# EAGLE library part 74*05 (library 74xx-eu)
Hex INVERTER, open collector

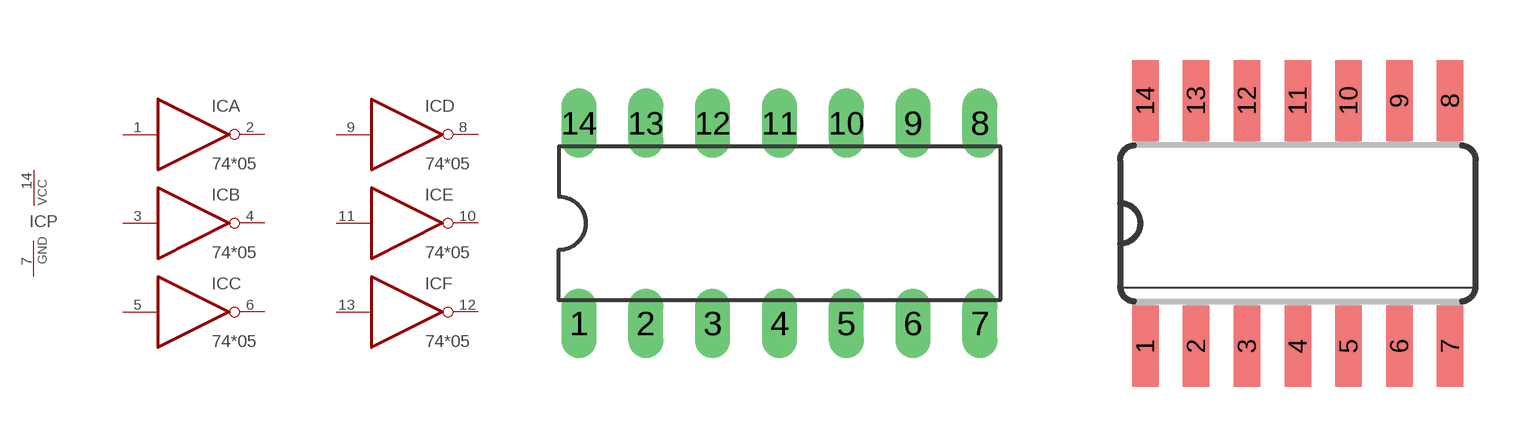
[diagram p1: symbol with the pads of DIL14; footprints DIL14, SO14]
Designator prefix IC; gates A=7405 B=7405 C=7405 D=7405 E=7405 F=7405 P=PWRN

## 7405N, 74ALS05N, 74HCT05N, 74LS05N, 74S05N  [DIL14]
1  A:I  in
2  A:O  oc
3  B:I  in
4  B:O  oc
5  C:I  in
6  C:O  oc
7  P:GND  pwr
8  D:O  oc
9  D:I  in
10  E:O  oc
11  E:I  in
12  F:O  oc
13  F:I  in
14  P:VCC  pwr

## 7405D, 74ALS05D, 74HCT05D, 74LS05D, 74S05D  [SO14]
Pads as for DIL14

## 7405FK, 74ALS05FK, 74HCT05FK, 74LS05FK, 74S05FK  [LCC20]
2  A:I  in
3  A:O  oc
4  B:I  in
6  B:O  oc
8  C:I  in
9  C:O  oc
10  P:GND  pwr
12  D:O  oc
13  D:I  in
14  E:O  oc
16  E:I  in
18  F:O  oc
19  F:I  in
20  P:VCC  pwr

## Footprint DIL14 (pad centres in mm)
Dual In Line Package
drill 0.813 long: 1 -7.62,-3.81; 2 -5.08,-3.81; 3 -2.54,-3.81; 4 0,-3.81; 5 2.54,-3.81; 6 5.08,-3.81; 7 7.62,-3.81; 8 7.62,3.81; 9 5.08,3.81; 10 2.54,3.81; 11 0,3.81; 12 -2.54,3.81; 13 -5.08,3.81; 14 -7.62,3.81

## Footprint SO14 (pad centres in mm)
Small Outline package 150 mil
smd 0.66 x 2.032: 1 -3.81,-3.073; 2 -2.54,-3.073; 3 -1.27,-3.073; 4 0,-3.073; 5 1.27,-3.073; 6 2.54,-3.073; 7 3.81,-3.073; 8 3.81,3.073; 9 2.54,3.073; 10 1.27,3.073; 11 0,3.073; 12 -1.27,3.073; 13 -2.54,3.073; 14 -3.81,3.073

## Footprint LCC20 (pad centres in mm)
Leadless Chip Carrier Ceramic Package
smd 0.8 x 3.4: 1 0,3.8
smd 0.8 x 2: 2 -1.27,4.5; 3 -2.54,4.5; 9 -2.54,-4.5; 10 -1.27,-4.5; 11 0,-4.5; 12 1.27,-4.5; 13 2.54,-4.5; 19 2.54,4.5; 20 1.27,4.5
smd 2 x 0.8: 4 -4.5,2.54; 5 -4.5,1.27; 6 -4.5,0; 7 -4.5,-1.27; 8 -4.5,-2.54; 14 4.5,-2.54; 15 4.5,-1.27; 16 4.5,0; 17 4.5,1.27; 18 4.5,2.54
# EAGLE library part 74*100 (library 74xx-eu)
8-bit bistable LATCH

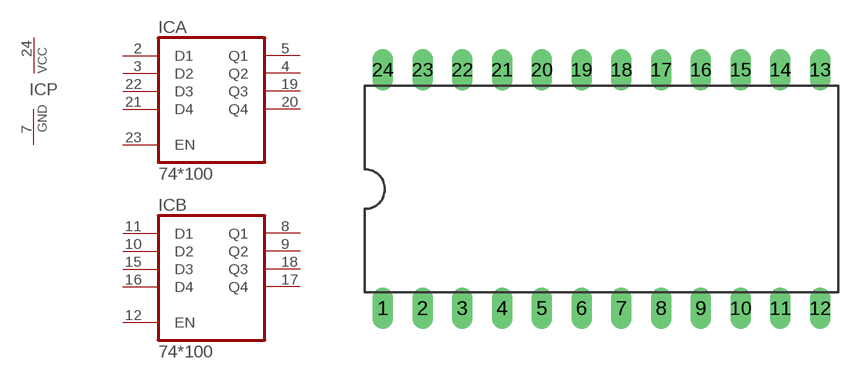
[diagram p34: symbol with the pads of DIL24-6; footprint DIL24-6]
Designator prefix IC; gates A=74100 B=74100 P=PWRN

## 74100N  [DIL24-6]
2  A:D1  in
3  A:D2  in
4  A:Q2  out
5  A:Q1  out
7  P:GND  pwr
8  B:Q1  out
9  B:Q2  out
10  B:D2  in
11  B:D1  in
12  B:EN  in
15  B:D3  in
16  B:D4  in
17  B:Q4  out
18  B:Q3  out
19  A:Q3  out
20  A:Q4  out
21  A:D4  in
22  A:D3  in
23  A:EN  in
24  P:VCC  pwr

## Footprint DIL24-6 (pad centres in mm)
Dual In Line Package 0.6 inch
drill 0.813 long: 1 -13.97,-7.62; 2 -11.43,-7.62; 3 -8.89,-7.62; 4 -6.35,-7.62; 5 -3.81,-7.62; 6 -1.27,-7.62; 7 1.27,-7.62; 8 3.81,-7.62; 9 6.35,-7.62; 10 8.89,-7.62; 11 11.43,-7.62; 12 13.97,-7.62; 13 13.97,7.62; 14 11.43,7.62; 15 8.89,7.62; 16 6.35,7.62; 17 3.81,7.62; 18 1.27,7.62; 19 -1.27,7.62; 20 -3.81,7.62; 21 -6.35,7.62; 22 -8.89,7.62; 23 -11.43,7.62; 24 -13.97,7.62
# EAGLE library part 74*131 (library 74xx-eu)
3-line to 8-line DECODER/DEMULTIPLEXER, address register

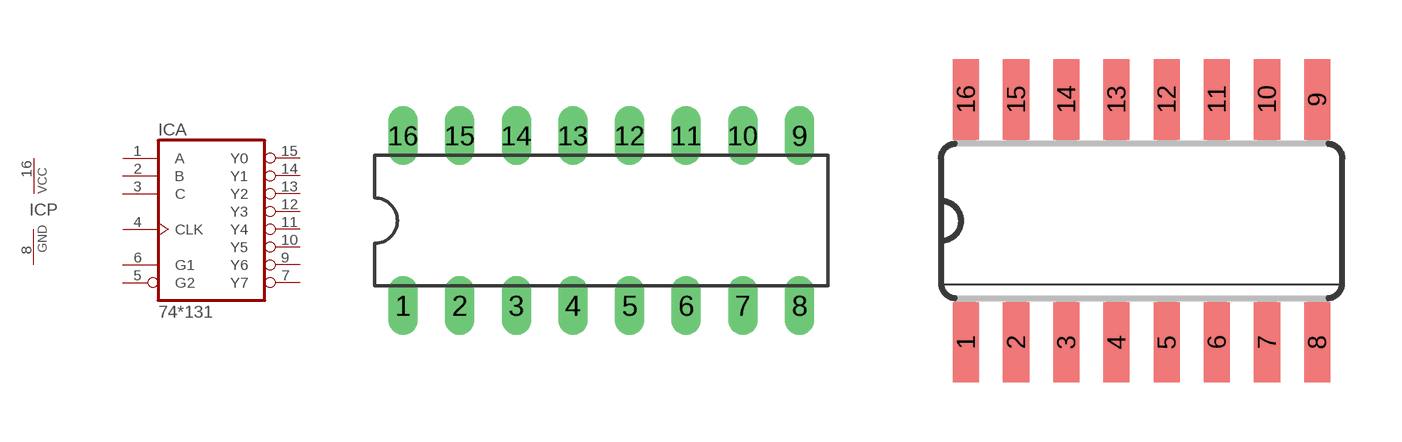
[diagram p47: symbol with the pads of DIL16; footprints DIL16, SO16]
Designator prefix IC; gates A=74131 P=PWRN

## 74131N, 74HC131N  [DIL16]
1  A:A  in
2  A:B  in
3  A:C  in
4  A:CLK  in
5  A:G2  in
6  A:G1  in
7  A:Y7  out
8  P:GND  pwr
9  A:Y6  out
10  A:Y5  out
11  A:Y4  out
12  A:Y3  out
13  A:Y2  out
14  A:Y1  out
15  A:Y0  out
16  P:VCC  pwr

## 74HC131D  [SO16]
Pads as for DIL16

## Footprint DIL16 (pad centres in mm)
Dual In Line Package
drill 0.813 long: 1 -8.89,-3.81; 2 -6.35,-3.81; 3 -3.81,-3.81; 4 -1.27,-3.81; 5 1.27,-3.81; 6 3.81,-3.81; 7 6.35,-3.81; 8 8.89,-3.81; 9 8.89,3.81; 10 6.35,3.81; 11 3.81,3.81; 12 1.27,3.81; 13 -1.27,3.81; 14 -3.81,3.81; 15 -6.35,3.81; 16 -8.89,3.81

## Footprint SO16 (pad centres in mm)
Small Outline package 150 mil
smd 0.66 x 2.032: 1 -4.445,-3.073; 2 -3.175,-3.073; 3 -1.905,-3.073; 4 -0.635,-3.073; 5 0.635,-3.073; 6 1.905,-3.073; 7 3.175,-3.073; 8 4.445,-3.073; 9 4.445,3.073; 10 3.175,3.073; 11 1.905,3.073; 12 0.635,3.073; 13 -0.635,3.073; 14 -1.905,3.073; 15 -3.175,3.073; 16 -4.445,3.073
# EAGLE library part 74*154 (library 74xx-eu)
4-line to 16-line data SELECTOR/MULTIPLEXER

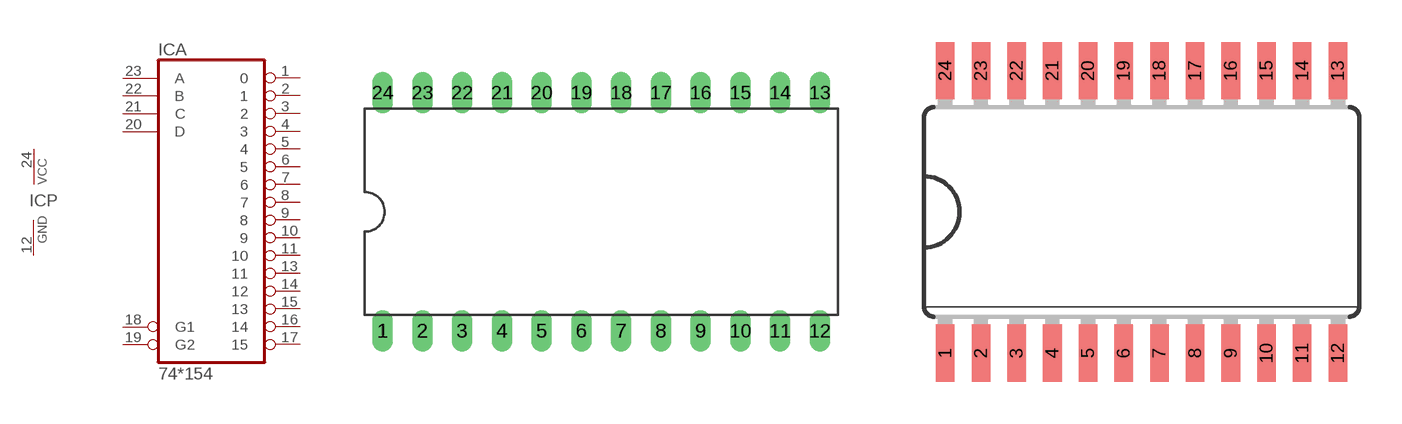
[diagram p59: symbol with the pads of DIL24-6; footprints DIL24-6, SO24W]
Designator prefix IC; gates A=74154 P=PWRN

## 74154N, 74HC154N, 74HCT154N  [DIL24-6]
1  A:0  out
2  A:1  out
3  A:2  out
4  A:3  out
5  A:4  out
6  A:5  out
7  A:6  out
8  A:7  out
9  A:8  out
10  A:9  out
11  A:10  out
12  P:GND  pwr
13  A:11  out
14  A:12  out
15  A:13  out
16  A:14  out
17  A:15  out
18  A:G1  in
19  A:G2  in
20  A:D  in
21  A:C  in
22  A:B  in
23  A:A  in
24  P:VCC  pwr

## 74154DW, 74HC154DW, 74HCT154DW  [SO24W]
Pads as for DIL24-6

## Footprint DIL24-6 (pad centres in mm)
Dual In Line Package 0.6 inch
drill 0.813 long: 1 -13.97,-7.62; 2 -11.43,-7.62; 3 -8.89,-7.62; 4 -6.35,-7.62; 5 -3.81,-7.62; 6 -1.27,-7.62; 7 1.27,-7.62; 8 3.81,-7.62; 9 6.35,-7.62; 10 8.89,-7.62; 11 11.43,-7.62; 12 13.97,-7.62; 13 13.97,7.62; 14 11.43,7.62; 15 8.89,7.62; 16 6.35,7.62; 17 3.81,7.62; 18 1.27,7.62; 19 -1.27,7.62; 20 -3.81,7.62; 21 -6.35,7.62; 22 -8.89,7.62; 23 -11.43,7.62; 24 -13.97,7.62

## Footprint SO24W (pad centres in mm)
Wide Small Outline package 300 mil
smd 0.66 x 2.032: 1 -6.985,-5.029; 2 -5.715,-5.029; 3 -4.445,-5.029; 4 -3.175,-5.029; 5 -1.905,-5.029; 6 -0.635,-5.029; 7 0.635,-5.029; 8 1.905,-5.029; 9 3.175,-5.029; 10 4.445,-5.029; 11 5.715,-5.029; 12 6.985,-5.029; 13 6.985,5.029; 14 5.715,5.029; 15 4.445,5.029; 16 3.175,5.029; 17 1.905,5.029; 18 0.635,5.029; 19 -0.635,5.029; 20 -1.905,5.029; 21 -3.175,5.029; 22 -4.445,5.029; 23 -5.715,5.029; 24 -6.985,5.029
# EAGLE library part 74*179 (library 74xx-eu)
4-bit parallel access SHIFT REGISTER

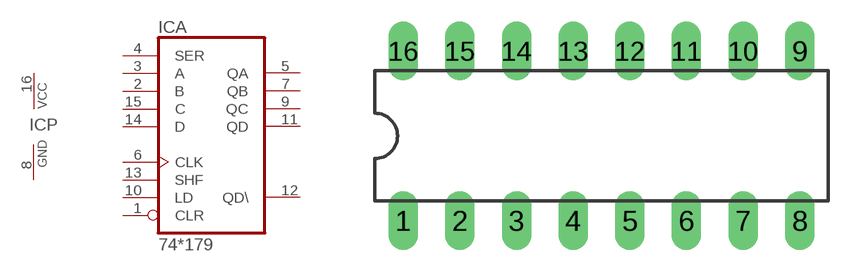
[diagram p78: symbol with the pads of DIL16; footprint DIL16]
Designator prefix IC; gates A=74179 P=PWRN

## 74179N  [DIL16]
1  A:CLR  in
2  A:B  in
3  A:A  in
4  A:SER  in
5  A:QA  out
6  A:CLK  in
7  A:QB  out
8  P:GND  pwr
9  A:QC  out
10  A:LD  in
11  A:QD  out
12  A:QD\  out
13  A:SHF  in
14  A:D  in
15  A:C  in
16  P:VCC  pwr

## Footprint DIL16 (pad centres in mm)
Dual In Line Package
drill 0.813 long: 1 -8.89,-3.81; 2 -6.35,-3.81; 3 -3.81,-3.81; 4 -1.27,-3.81; 5 1.27,-3.81; 6 3.81,-3.81; 7 6.35,-3.81; 8 8.89,-3.81; 9 8.89,3.81; 10 6.35,3.81; 11 3.81,3.81; 12 1.27,3.81; 13 -1.27,3.81; 14 -3.81,3.81; 15 -6.35,3.81; 16 -8.89,3.81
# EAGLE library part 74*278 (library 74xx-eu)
4-bit cascadable PRIORITY REGISTER

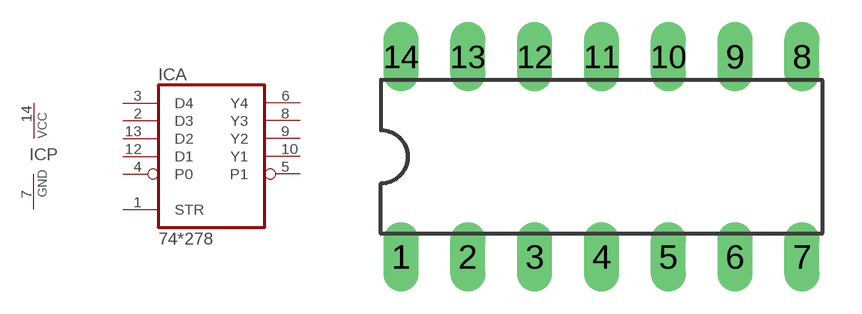
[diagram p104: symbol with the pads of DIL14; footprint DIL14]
Designator prefix IC; gates A=74278 P=PWRN

## 74278N  [DIL14]
1  A:STR  in
2  A:D3  in
3  A:D4  in
4  A:P0  in
5  A:P1  out
6  A:Y4  out
7  P:GND  pwr
8  A:Y3  out
9  A:Y2  out
10  A:Y1  out
12  A:D1  in
13  A:D2  in
14  P:VCC  pwr

## Footprint DIL14 (pad centres in mm)
Dual In Line Package
drill 0.813 long: 1 -7.62,-3.81; 2 -5.08,-3.81; 3 -2.54,-3.81; 4 0,-3.81; 5 2.54,-3.81; 6 5.08,-3.81; 7 7.62,-3.81; 8 7.62,3.81; 9 5.08,3.81; 10 2.54,3.81; 11 0,3.81; 12 -2.54,3.81; 13 -5.08,3.81; 14 -7.62,3.81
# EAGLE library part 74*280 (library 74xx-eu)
9-bit odd/even PARITY GENERATOR/CHECKER

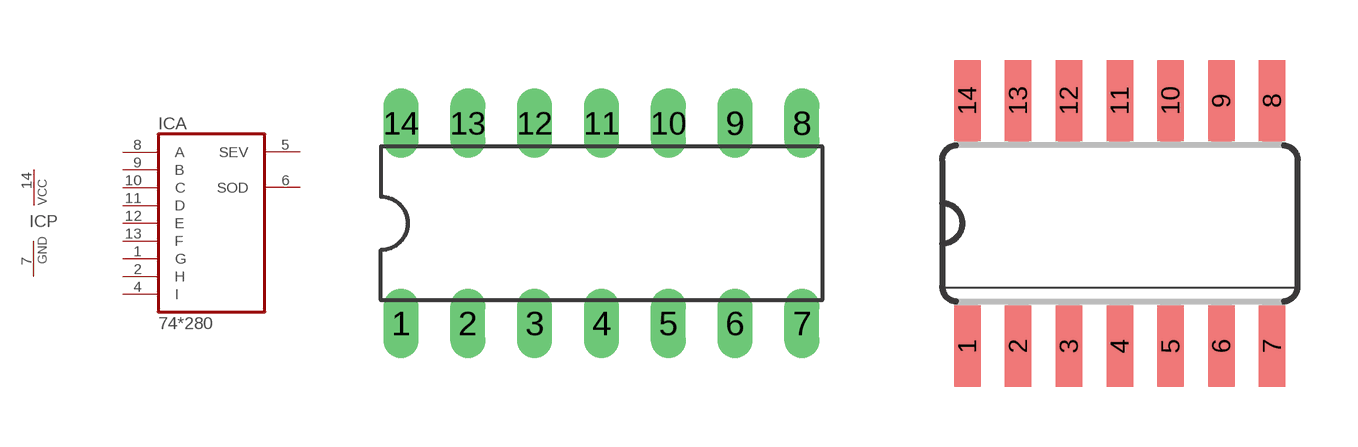
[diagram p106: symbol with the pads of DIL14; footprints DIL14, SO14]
Designator prefix IC; gates A=74280 P=PWRN

## 74AC280N, 74ACT280N, 74HC280N, 74HCT280N, 74LS280N, 74S280N  [DIL14]
1  A:G  in
2  A:H  in
4  A:I  in
5  A:SEV  out
6  A:SOD  out
7  P:GND  pwr
8  A:A  in
9  A:B  in
10  A:C  in
11  A:D  in
12  A:E  in
13  A:F  in
14  P:VCC  pwr

## 74AC280D, 74ACT280D, 74HC280D, 74HCT280D, 74LS280D, 74S280D  [SO14]
Pads as for DIL14

## 74AC280FK, 74ACT280FK, 74HC280FK, 74HCT280FK, 74LS280FK, 74S280FK  [LCC20]
2  A:G  in
3  A:H  in
6  A:I  in
8  A:SEV  out
9  A:SOD  out
10  P:GND  pwr
12  A:A  in
13  A:B  in
14  A:C  in
16  A:D  in
18  A:E  in
19  A:F  in
20  P:VCC  pwr

## Footprint DIL14 (pad centres in mm)
Dual In Line Package
drill 0.813 long: 1 -7.62,-3.81; 2 -5.08,-3.81; 3 -2.54,-3.81; 4 0,-3.81; 5 2.54,-3.81; 6 5.08,-3.81; 7 7.62,-3.81; 8 7.62,3.81; 9 5.08,3.81; 10 2.54,3.81; 11 0,3.81; 12 -2.54,3.81; 13 -5.08,3.81; 14 -7.62,3.81

## Footprint SO14 (pad centres in mm)
Small Outline package 150 mil
smd 0.66 x 2.032: 1 -3.81,-3.073; 2 -2.54,-3.073; 3 -1.27,-3.073; 4 0,-3.073; 5 1.27,-3.073; 6 2.54,-3.073; 7 3.81,-3.073; 8 3.81,3.073; 9 2.54,3.073; 10 1.27,3.073; 11 0,3.073; 12 -1.27,3.073; 13 -2.54,3.073; 14 -3.81,3.073

## Footprint LCC20 (pad centres in mm)
Leadless Chip Carrier Ceramic Package
smd 0.8 x 3.4: 1 0,3.8
smd 0.8 x 2: 2 -1.27,4.5; 3 -2.54,4.5; 9 -2.54,-4.5; 10 -1.27,-4.5; 11 0,-4.5; 12 1.27,-4.5; 13 2.54,-4.5; 19 2.54,4.5; 20 1.27,4.5
smd 2 x 0.8: 4 -4.5,2.54; 5 -4.5,1.27; 6 -4.5,0; 7 -4.5,-1.27; 8 -4.5,-2.54; 14 4.5,-2.54; 15 4.5,-1.27; 16 4.5,0; 17 4.5,1.27; 18 4.5,2.54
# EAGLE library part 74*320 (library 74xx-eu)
Crystal controlled OSCILLATOR

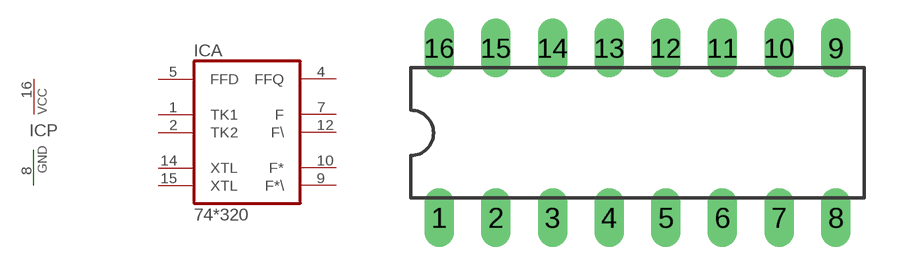
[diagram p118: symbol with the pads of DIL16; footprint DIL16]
Designator prefix IC; gates A=74320 P=PWRN

## 74320N  [DIL16]
1  A:TK1  in
2  A:TK2  in
4  A:FFQ  out
5  A:FFD  in
7  A:F  out
8  P:GND  pwr
9  A:F*\  out
10  A:F*  out
12  A:F\  out
14  A:XTL  in
15  A:XTL  in
16  P:VCC  pwr

## Footprint DIL16 (pad centres in mm)
Dual In Line Package
drill 0.813 long: 1 -8.89,-3.81; 2 -6.35,-3.81; 3 -3.81,-3.81; 4 -1.27,-3.81; 5 1.27,-3.81; 6 3.81,-3.81; 7 6.35,-3.81; 8 8.89,-3.81; 9 8.89,3.81; 10 6.35,3.81; 11 3.81,3.81; 12 1.27,3.81; 13 -1.27,3.81; 14 -3.81,3.81; 15 -6.35,3.81; 16 -8.89,3.81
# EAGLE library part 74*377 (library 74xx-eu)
Octal D type FLIP FLOP, enable

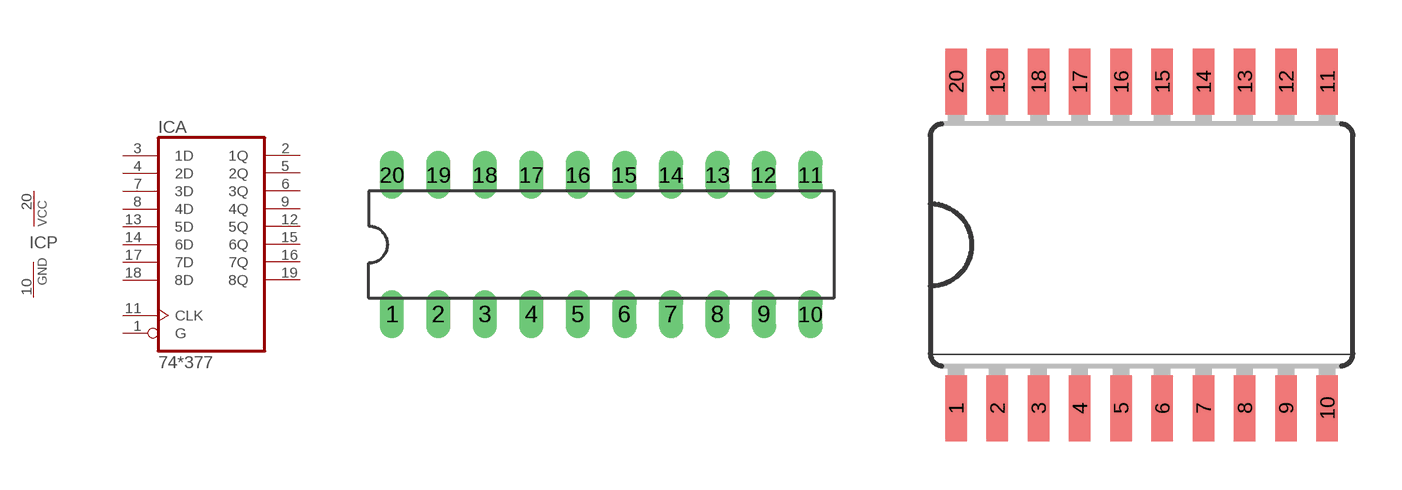
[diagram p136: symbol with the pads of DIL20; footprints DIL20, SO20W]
Designator prefix IC; gates A=74377 P=PWRN

## 74AC377N, 74ACT377N, 74HC377N, 74HCT377N, 74LS377N  [DIL20]
1  A:G  in
2  A:1Q  out
3  A:1D  in
4  A:2D  in
5  A:2Q  out
6  A:3Q  out
7  A:3D  in
8  A:4D  in
9  A:4Q  out
10  P:GND  pwr
11  A:CLK  in
12  A:5Q  out
13  A:5D  in
14  A:6D  in
15  A:6Q  out
16  A:7Q  out
17  A:7D  in
18  A:8D  in
19  A:8Q  out
20  P:VCC  pwr

## 74AC377DW, 74ACT377DW, 74HC377DW, 74HCT377DW  [SO20W]
Pads as for DIL20

## 74AC377FK, 74ACT377FK, 74HC377FK, 74HCT377FK, 74LS377FK  [LCC20]
Pads as for DIL20

## Footprint DIL20 (pad centres in mm)
Dual In Line Package
drill 0.813 long: 1 -11.43,-3.81; 2 -8.89,-3.81; 3 -6.35,-3.81; 4 -3.81,-3.81; 5 -1.27,-3.81; 6 1.27,-3.81; 7 3.81,-3.81; 8 6.35,-3.81; 9 8.89,-3.81; 10 11.43,-3.81; 11 11.43,3.81; 12 8.89,3.81; 13 6.35,3.81; 14 3.81,3.81; 15 1.27,3.81; 16 -1.27,3.81; 17 -3.81,3.81; 18 -6.35,3.81; 19 -8.89,3.81; 20 -11.43,3.81

## Footprint SO20W (pad centres in mm)
Wide Small Outline package 300 mil
smd 0.66 x 2.032: 1 -5.715,-5.029; 2 -4.445,-5.029; 3 -3.175,-5.029; 4 -1.905,-5.029; 5 -0.635,-5.029; 6 0.635,-5.029; 7 1.905,-5.029; 8 3.175,-5.029; 9 4.445,-5.029; 10 5.715,-5.029; 11 5.715,5.029; 12 4.445,5.029; 13 3.175,5.029; 14 1.905,5.029; 15 0.635,5.029; 16 -0.635,5.029; 17 -1.905,5.029; 18 -3.175,5.029; 19 -4.445,5.029; 20 -5.715,5.029

## Footprint LCC20 (pad centres in mm)
Leadless Chip Carrier Ceramic Package
smd 0.8 x 3.4: 1 0,3.8
smd 0.8 x 2: 2 -1.27,4.5; 3 -2.54,4.5; 9 -2.54,-4.5; 10 -1.27,-4.5; 11 0,-4.5; 12 1.27,-4.5; 13 2.54,-4.5; 19 2.54,4.5; 20 1.27,4.5
smd 2 x 0.8: 4 -4.5,2.54; 5 -4.5,1.27; 6 -4.5,0; 7 -4.5,-1.27; 8 -4.5,-2.54; 14 4.5,-2.54; 15 4.5,-1.27; 16 4.5,0; 17 4.5,1.27; 18 4.5,2.54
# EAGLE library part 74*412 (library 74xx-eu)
Multi mode buffered LATCH

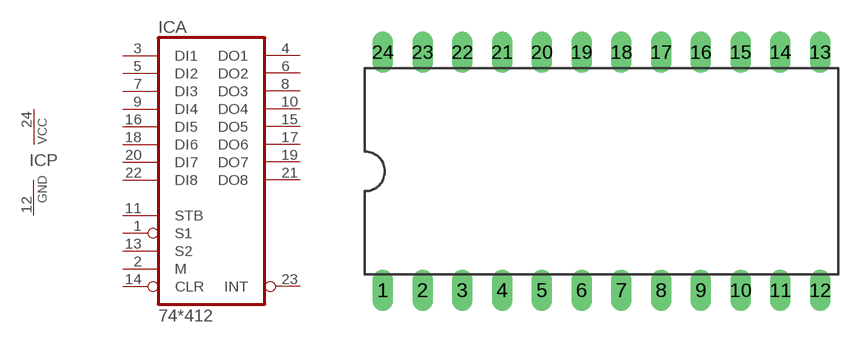
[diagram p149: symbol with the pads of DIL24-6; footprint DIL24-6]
Designator prefix IC; gates A=74412 P=PWRN

## 74412N  [DIL24-6]
1  A:S1  in
2  A:M  in
3  A:DI1  in
4  A:DO1  hiz
5  A:DI2  in
6  A:DO2  hiz
7  A:DI3  in
8  A:DO3  hiz
9  A:DI4  in
10  A:DO4  hiz
11  A:STB  in
12  P:GND  pwr
13  A:S2  in
14  A:CLR  in
15  A:DO5  hiz
16  A:DI5  in
17  A:DO6  hiz
18  A:DI6  in
19  A:DO7  hiz
20  A:DI7  in
21  A:DO8  hiz
22  A:DI8  in
23  A:INT  out
24  P:VCC  pwr

## Footprint DIL24-6 (pad centres in mm)
Dual In Line Package 0.6 inch
drill 0.813 long: 1 -13.97,-7.62; 2 -11.43,-7.62; 3 -8.89,-7.62; 4 -6.35,-7.62; 5 -3.81,-7.62; 6 -1.27,-7.62; 7 1.27,-7.62; 8 3.81,-7.62; 9 6.35,-7.62; 10 8.89,-7.62; 11 11.43,-7.62; 12 13.97,-7.62; 13 13.97,7.62; 14 11.43,7.62; 15 8.89,7.62; 16 6.35,7.62; 17 3.81,7.62; 18 1.27,7.62; 19 -1.27,7.62; 20 -3.81,7.62; 21 -6.35,7.62; 22 -8.89,7.62; 23 -11.43,7.62; 24 -13.97,7.62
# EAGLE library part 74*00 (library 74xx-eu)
Quad 2-input NAND gate

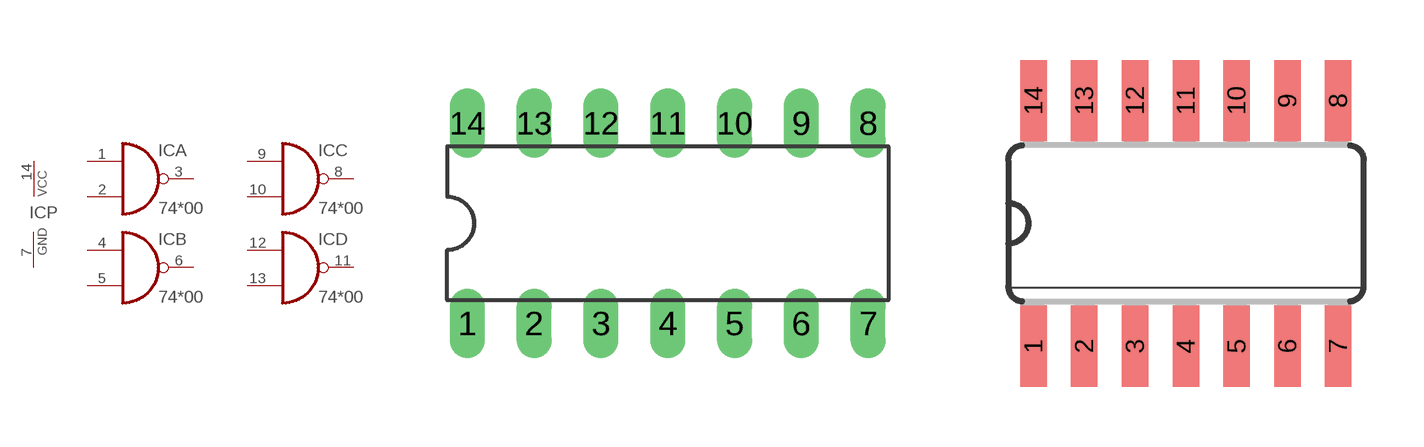
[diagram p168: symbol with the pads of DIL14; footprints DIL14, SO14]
Designator prefix IC; gates A=7400 B=7400 C=7400 D=7400 P=PWRN

## 7400N, 74AC00N, 74ACT00N, 74ALS00N, 74AS00N, 74HC00N, 74HCT00N, 74LS00N, 74S00N  [DIL14]
1  A:I0  in
2  A:I1  in
3  A:O  out
4  B:I0  in
5  B:I1  in
6  B:O  out
7  P:GND  pwr
8  C:O  out
9  C:I0  in
10  C:I1  in
11  D:O  out
12  D:I0  in
13  D:I1  in
14  P:VCC  pwr

## 7400D, 74AC00D, 74ACT00D, 74ALS00D, 74AS00D, 74HC00D, 74HCT00D, 74LS00D, 74S00D  [SO14]
Pads as for DIL14

## 7400FK, 74AC00FK, 74ACT00FK, 74ALS00FK, 74AS00FK, 74HC00FK, 74HCT00FK, 74LS00FK, 74S00FK  [LCC20]
2  A:I0  in
3  A:I1  in
4  A:O  out
6  B:I0  in
8  B:I1  in
9  B:O  out
10  P:GND  pwr
12  C:O  out
13  C:I0  in
14  C:I1  in
16  D:O  out
18  D:I0  in
19  D:I1  in
20  P:VCC  pwr

## Footprint DIL14 (pad centres in mm)
Dual In Line Package
drill 0.813 long: 1 -7.62,-3.81; 2 -5.08,-3.81; 3 -2.54,-3.81; 4 0,-3.81; 5 2.54,-3.81; 6 5.08,-3.81; 7 7.62,-3.81; 8 7.62,3.81; 9 5.08,3.81; 10 2.54,3.81; 11 0,3.81; 12 -2.54,3.81; 13 -5.08,3.81; 14 -7.62,3.81

## Footprint SO14 (pad centres in mm)
Small Outline package 150 mil
smd 0.66 x 2.032: 1 -3.81,-3.073; 2 -2.54,-3.073; 3 -1.27,-3.073; 4 0,-3.073; 5 1.27,-3.073; 6 2.54,-3.073; 7 3.81,-3.073; 8 3.81,3.073; 9 2.54,3.073; 10 1.27,3.073; 11 0,3.073; 12 -1.27,3.073; 13 -2.54,3.073; 14 -3.81,3.073

## Footprint LCC20 (pad centres in mm)
Leadless Chip Carrier Ceramic Package
smd 0.8 x 3.4: 1 0,3.8
smd 0.8 x 2: 2 -1.27,4.5; 3 -2.54,4.5; 9 -2.54,-4.5; 10 -1.27,-4.5; 11 0,-4.5; 12 1.27,-4.5; 13 2.54,-4.5; 19 2.54,4.5; 20 1.27,4.5
smd 2 x 0.8: 4 -4.5,2.54; 5 -4.5,1.27; 6 -4.5,0; 7 -4.5,-1.27; 8 -4.5,-2.54; 14 4.5,-2.54; 15 4.5,-1.27; 16 4.5,0; 17 4.5,1.27; 18 4.5,2.54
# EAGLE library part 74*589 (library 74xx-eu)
8-bit SHIFT REGISTER, input latch, 3-state

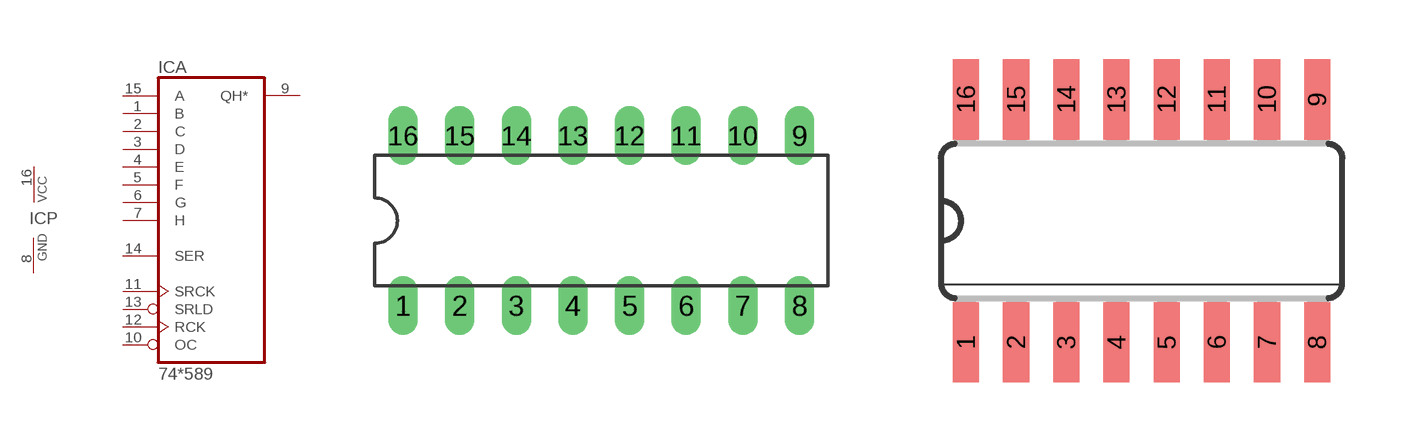
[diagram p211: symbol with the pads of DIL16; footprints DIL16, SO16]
Designator prefix IC; gates A=74589 P=PWRN

## 74589N, 74HC589N  [DIL16]
1  A:B  in
2  A:C  in
3  A:D  in
4  A:E  in
5  A:F  in
6  A:G  in
7  A:H  in
8  P:GND  pwr
9  A:QH*  hiz
10  A:OC  in
11  A:SRCK  in
12  A:RCK  in
13  A:SRLD  in
14  A:SER  in
15  A:A  in
16  P:VCC  pwr

## 74HC589D  [SO16]
Pads as for DIL16

## Footprint DIL16 (pad centres in mm)
Dual In Line Package
drill 0.813 long: 1 -8.89,-3.81; 2 -6.35,-3.81; 3 -3.81,-3.81; 4 -1.27,-3.81; 5 1.27,-3.81; 6 3.81,-3.81; 7 6.35,-3.81; 8 8.89,-3.81; 9 8.89,3.81; 10 6.35,3.81; 11 3.81,3.81; 12 1.27,3.81; 13 -1.27,3.81; 14 -3.81,3.81; 15 -6.35,3.81; 16 -8.89,3.81

## Footprint SO16 (pad centres in mm)
Small Outline package 150 mil
smd 0.66 x 2.032: 1 -4.445,-3.073; 2 -3.175,-3.073; 3 -1.905,-3.073; 4 -0.635,-3.073; 5 0.635,-3.073; 6 1.905,-3.073; 7 3.175,-3.073; 8 4.445,-3.073; 9 4.445,3.073; 10 3.175,3.073; 11 1.905,3.073; 12 0.635,3.073; 13 -0.635,3.073; 14 -1.905,3.073; 15 -3.175,3.073; 16 -4.445,3.073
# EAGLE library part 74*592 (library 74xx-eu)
8-bit binary COUNTER, input register

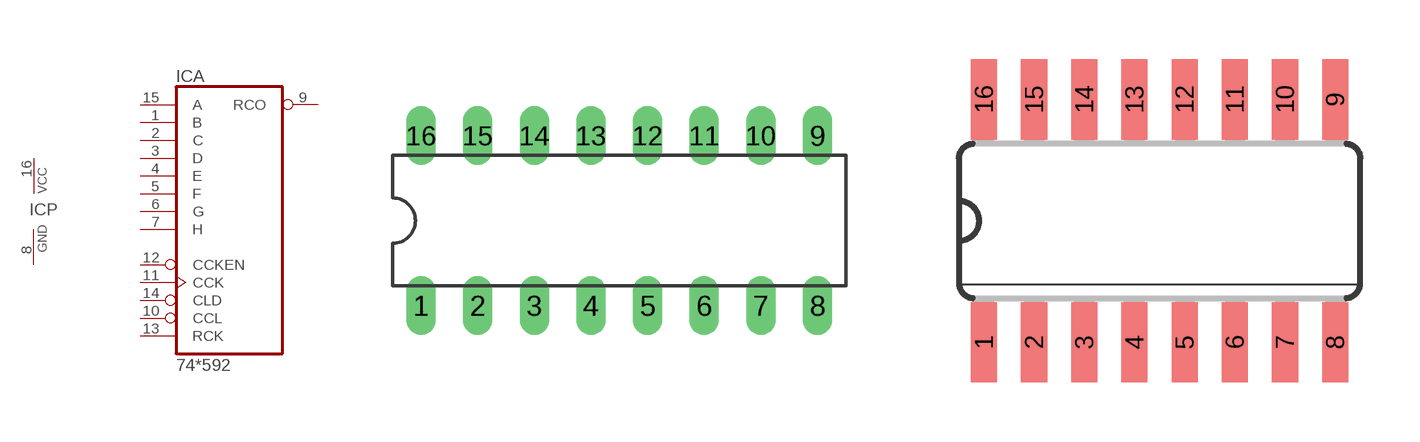
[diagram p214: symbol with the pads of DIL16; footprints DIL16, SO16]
Designator prefix IC; gates A=74592 P=PWRN

## 74HC592N, 74LS592N  [DIL16]
1  A:B  in
2  A:C  in
3  A:D  in
4  A:E  in
5  A:F  in
6  A:G  in
7  A:H  in
8  P:GND  pwr
9  A:RCO  out
10  A:CCL  in
11  A:CCK  in
12  A:CCKEN  in
13  A:RCK  in
14  A:CLD  in
15  A:A  in
16  P:VCC  pwr

## 74HC592D, 74LS592D  [SO16]
Pads as for DIL16

## 74HC592FK, 74LS592FK  [LCC20]
2  A:B  in
3  A:C  in
4  A:D  in
5  A:E  in
7  A:F  in
8  A:G  in
9  A:H  in
10  P:GND  pwr
12  A:RCO  out
13  A:CCL  in
14  A:CCK  in
15  A:CCKEN  in
17  A:RCK  in
18  A:CLD  in
19  A:A  in
20  P:VCC  pwr

## Footprint DIL16 (pad centres in mm)
Dual In Line Package
drill 0.813 long: 1 -8.89,-3.81; 2 -6.35,-3.81; 3 -3.81,-3.81; 4 -1.27,-3.81; 5 1.27,-3.81; 6 3.81,-3.81; 7 6.35,-3.81; 8 8.89,-3.81; 9 8.89,3.81; 10 6.35,3.81; 11 3.81,3.81; 12 1.27,3.81; 13 -1.27,3.81; 14 -3.81,3.81; 15 -6.35,3.81; 16 -8.89,3.81

## Footprint SO16 (pad centres in mm)
Small Outline package 150 mil
smd 0.66 x 2.032: 1 -4.445,-3.073; 2 -3.175,-3.073; 3 -1.905,-3.073; 4 -0.635,-3.073; 5 0.635,-3.073; 6 1.905,-3.073; 7 3.175,-3.073; 8 4.445,-3.073; 9 4.445,3.073; 10 3.175,3.073; 11 1.905,3.073; 12 0.635,3.073; 13 -0.635,3.073; 14 -1.905,3.073; 15 -3.175,3.073; 16 -4.445,3.073

## Footprint LCC20 (pad centres in mm)
Leadless Chip Carrier Ceramic Package
smd 0.8 x 3.4: 1 0,3.8
smd 0.8 x 2: 2 -1.27,4.5; 3 -2.54,4.5; 9 -2.54,-4.5; 10 -1.27,-4.5; 11 0,-4.5; 12 1.27,-4.5; 13 2.54,-4.5; 19 2.54,4.5; 20 1.27,4.5
smd 2 x 0.8: 4 -4.5,2.54; 5 -4.5,1.27; 6 -4.5,0; 7 -4.5,-1.27; 8 -4.5,-2.54; 14 4.5,-2.54; 15 4.5,-1.27; 16 4.5,0; 17 4.5,1.27; 18 4.5,2.54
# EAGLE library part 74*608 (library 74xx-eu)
MEMORY CYCLE CONTROLLER

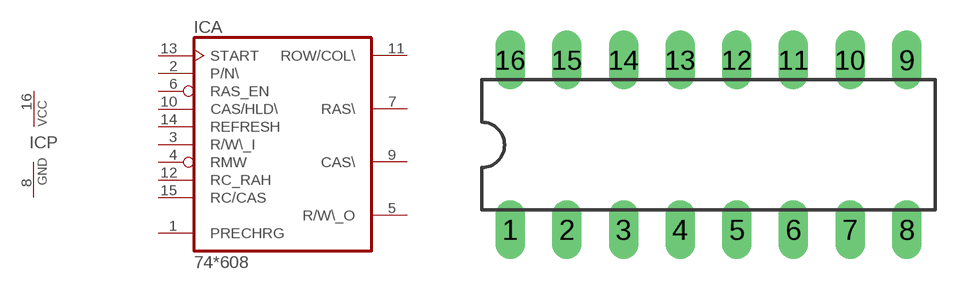
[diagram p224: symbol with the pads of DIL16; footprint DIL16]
Designator prefix IC; gates A=74608 P=PWRN

## 74608N  [DIL16]
1  A:PRECHRG  in
2  A:P/N\  in
3  A:R/W\_I  in
4  A:RMW  in
5  A:R/W\_O  out
6  A:RAS_EN  in
7  A:RAS\  out
8  P:GND  pwr
9  A:CAS\  out
10  A:CAS/HLD\  in
11  A:ROW/COL\  out
12  A:RC_RAH  in
13  A:START  in
14  A:REFRESH  in
15  A:RC/CAS  in
16  P:VCC  pwr

## Footprint DIL16 (pad centres in mm)
Dual In Line Package
drill 0.813 long: 1 -8.89,-3.81; 2 -6.35,-3.81; 3 -3.81,-3.81; 4 -1.27,-3.81; 5 1.27,-3.81; 6 3.81,-3.81; 7 6.35,-3.81; 8 8.89,-3.81; 9 8.89,3.81; 10 6.35,3.81; 11 3.81,3.81; 12 1.27,3.81; 13 -1.27,3.81; 14 -3.81,3.81; 15 -6.35,3.81; 16 -8.89,3.81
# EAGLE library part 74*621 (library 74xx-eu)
Octal BUS TRANSCEIVER, open collector

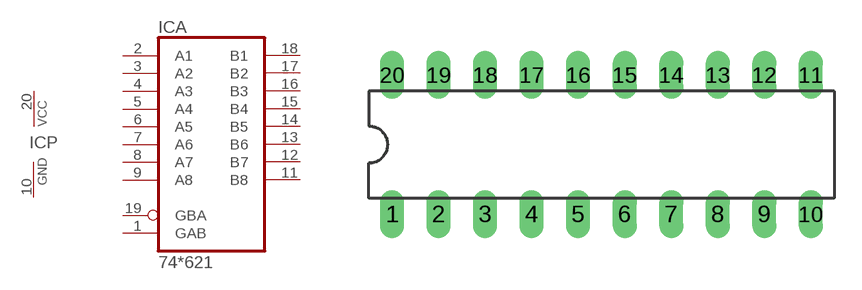
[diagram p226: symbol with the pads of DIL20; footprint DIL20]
Designator prefix IC; gates A=74621 P=PWRN

## 74621N  [DIL20]
1  A:GAB  in
2  A:A1  oc
3  A:A2  oc
4  A:A3  oc
5  A:A4  oc
6  A:A5  oc
7  A:A6  oc
8  A:A7  oc
9  A:A8  oc
10  P:GND  pwr
11  A:B8  oc
12  A:B7  oc
13  A:B6  oc
14  A:B5  oc
15  A:B4  oc
16  A:B3  oc
17  A:B2  oc
18  A:B1  oc
19  A:GBA  in
20  P:VCC  pwr

## Footprint DIL20 (pad centres in mm)
Dual In Line Package
drill 0.813 long: 1 -11.43,-3.81; 2 -8.89,-3.81; 3 -6.35,-3.81; 4 -3.81,-3.81; 5 -1.27,-3.81; 6 1.27,-3.81; 7 3.81,-3.81; 8 6.35,-3.81; 9 8.89,-3.81; 10 11.43,-3.81; 11 11.43,3.81; 12 8.89,3.81; 13 6.35,3.81; 14 3.81,3.81; 15 1.27,3.81; 16 -1.27,3.81; 17 -3.81,3.81; 18 -6.35,3.81; 19 -8.89,3.81; 20 -11.43,3.81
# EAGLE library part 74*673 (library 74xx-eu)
16-bit SHIFT REGISTER serial to parallel conversion

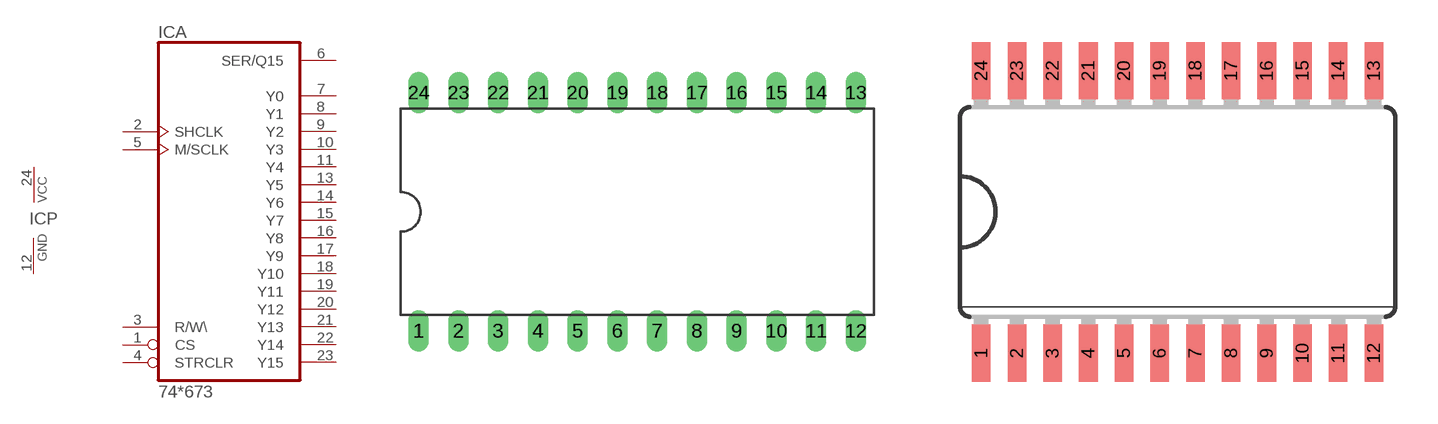
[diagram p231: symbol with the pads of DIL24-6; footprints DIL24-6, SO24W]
Designator prefix IC; gates A=74673 P=PWRN

## 74LS673N  [DIL24-6]
1  A:CS  in
2  A:SHCLK  in
3  A:R/W\  in
4  A:STRCLR  in
5  A:M/SCLK  in
6  A:SER/Q15
7  A:Y0  out
8  A:Y1  out
9  A:Y2  out
10  A:Y3  out
11  A:Y4  out
12  P:GND  pwr
13  A:Y5  out
14  A:Y6  out
15  A:Y7  out
16  A:Y8  out
17  A:Y9  out
18  A:Y10  out
19  A:Y11  out
20  A:Y12  out
21  A:Y13  out
22  A:Y14  out
23  A:Y15  out
24  P:VCC  pwr

## 74LS673DW  [SO24W]
Pads as for DIL24-6

## 74LS673FK  [LCC28]
2  A:CS  in
3  A:SHCLK  in
4  A:R/W\  in
5  A:STRCLR  in
6  A:M/SCLK  in
7  A:SER/Q15
9  A:Y0  out
10  A:Y1  out
11  A:Y2  out
12  A:Y3  out
13  A:Y4  out
14  P:GND  pwr
16  A:Y5  out
17  A:Y6  out
18  A:Y7  out
19  A:Y8  out
20  A:Y9  out
21  A:Y10  out
23  A:Y11  out
24  A:Y12  out
25  A:Y13  out
26  A:Y14  out
27  A:Y15  out
28  P:VCC  pwr

## Footprint DIL24-6 (pad centres in mm)
Dual In Line Package 0.6 inch
drill 0.813 long: 1 -13.97,-7.62; 2 -11.43,-7.62; 3 -8.89,-7.62; 4 -6.35,-7.62; 5 -3.81,-7.62; 6 -1.27,-7.62; 7 1.27,-7.62; 8 3.81,-7.62; 9 6.35,-7.62; 10 8.89,-7.62; 11 11.43,-7.62; 12 13.97,-7.62; 13 13.97,7.62; 14 11.43,7.62; 15 8.89,7.62; 16 6.35,7.62; 17 3.81,7.62; 18 1.27,7.62; 19 -1.27,7.62; 20 -3.81,7.62; 21 -6.35,7.62; 22 -8.89,7.62; 23 -11.43,7.62; 24 -13.97,7.62

## Footprint SO24W (pad centres in mm)
Wide Small Outline package 300 mil
smd 0.66 x 2.032: 1 -6.985,-5.029; 2 -5.715,-5.029; 3 -4.445,-5.029; 4 -3.175,-5.029; 5 -1.905,-5.029; 6 -0.635,-5.029; 7 0.635,-5.029; 8 1.905,-5.029; 9 3.175,-5.029; 10 4.445,-5.029; 11 5.715,-5.029; 12 6.985,-5.029; 13 6.985,5.029; 14 5.715,5.029; 15 4.445,5.029; 16 3.175,5.029; 17 1.905,5.029; 18 0.635,5.029; 19 -0.635,5.029; 20 -1.905,5.029; 21 -3.175,5.029; 22 -4.445,5.029; 23 -5.715,5.029; 24 -6.985,5.029

## Footprint LCC28 (pad centres in mm)
Leadless Chip Carrier Ceramic Package
smd 0.8 x 3.4: 1 0,5.1
smd 0.8 x 2: 2 -1.27,5.8; 3 -2.54,5.8; 4 -3.81,5.8; 12 -3.81,-5.8; 13 -2.54,-5.8; 14 -1.27,-5.8; 15 0,-5.8; 16 1.27,-5.8; 17 2.54,-5.8; 18 3.81,-5.8; 26 3.81,5.8; 27 2.54,5.8; 28 1.27,5.8
smd 2 x 0.8: 5 -5.8,3.81; 6 -5.8,2.54; 7 -5.8,1.27; 8 -5.8,0; 9 -5.8,-1.27; 10 -5.8,-2.54; 11 -5.8,-3.81; 19 5.8,-3.81; 20 5.8,-2.54; 21 5.8,-1.27; 22 5.8,0; 23 5.8,1.27; 24 5.8,2.54; 25 5.8,3.81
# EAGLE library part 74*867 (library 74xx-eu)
8-bit synchronous COUNTER

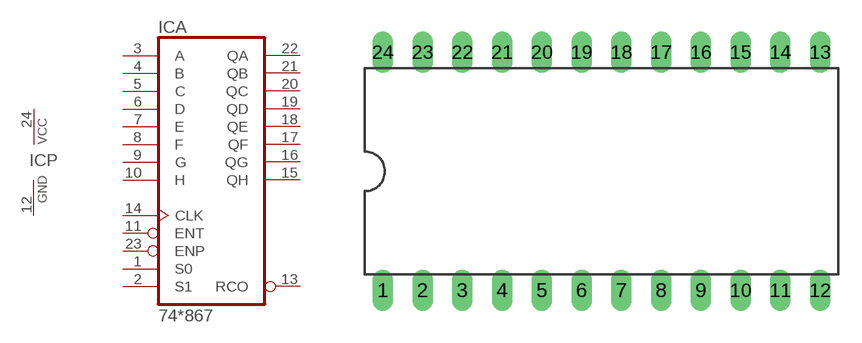
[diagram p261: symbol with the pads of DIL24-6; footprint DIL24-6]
Designator prefix IC; gates A=74867 P=PWRN

## 74AS867NT  [DIL24-6]
1  A:S0  in
2  A:S1  in
3  A:A  in
4  A:B  in
5  A:C  in
6  A:D  in
7  A:E  in
8  A:F  in
9  A:G  in
10  A:H  in
11  A:ENT  in
12  P:GND  pwr
13  A:RCO  out
14  A:CLK  in
15  A:QH  out
16  A:QG  out
17  A:QF  out
18  A:QE  out
19  A:QD  out
20  A:QC  out
21  A:QB  out
22  A:QA  out
23  A:ENP  in
24  P:VCC  pwr

## Footprint DIL24-6 (pad centres in mm)
Dual In Line Package 0.6 inch
drill 0.813 long: 1 -13.97,-7.62; 2 -11.43,-7.62; 3 -8.89,-7.62; 4 -6.35,-7.62; 5 -3.81,-7.62; 6 -1.27,-7.62; 7 1.27,-7.62; 8 3.81,-7.62; 9 6.35,-7.62; 10 8.89,-7.62; 11 11.43,-7.62; 12 13.97,-7.62; 13 13.97,7.62; 14 11.43,7.62; 15 8.89,7.62; 16 6.35,7.62; 17 3.81,7.62; 18 1.27,7.62; 19 -1.27,7.62; 20 -3.81,7.62; 21 -6.35,7.62; 22 -8.89,7.62; 23 -11.43,7.62; 24 -13.97,7.62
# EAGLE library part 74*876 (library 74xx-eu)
2 x 4-bit inverting D type FLIP FLOP

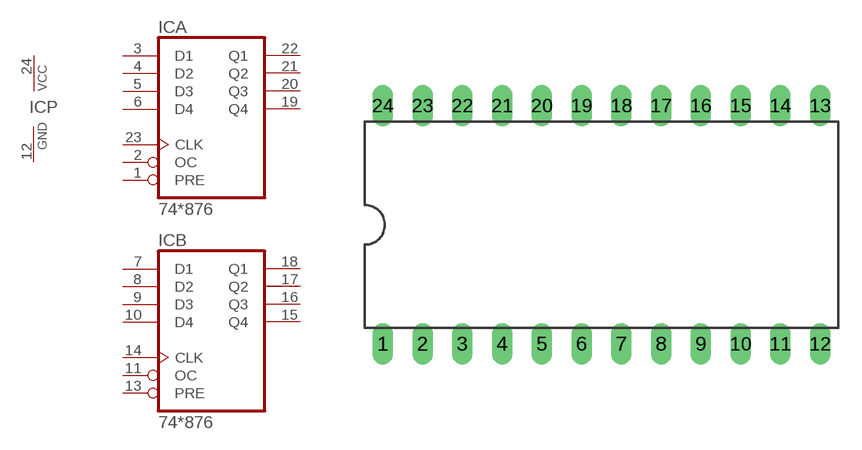
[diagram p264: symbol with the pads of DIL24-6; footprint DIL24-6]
Designator prefix IC; gates A=74876 B=74876 P=PWRN

## 74ALS876NT, 74AS876NT  [DIL24-6]
1  A:PRE  in
2  A:OC  in
3  A:D1  in
4  A:D2  in
5  A:D3  in
6  A:D4  in
7  B:D1  in
8  B:D2  in
9  B:D3  in
10  B:D4  in
11  B:OC  in
12  P:GND  pwr
13  B:PRE  in
14  B:CLK  in
15  B:Q4  hiz
16  B:Q3  hiz
17  B:Q2  hiz
18  B:Q1  hiz
19  A:Q4  hiz
20  A:Q3  hiz
21  A:Q2  hiz
22  A:Q1  hiz
23  A:CLK  in
24  P:VCC  pwr

## Footprint DIL24-6 (pad centres in mm)
Dual In Line Package 0.6 inch
drill 0.813 long: 1 -13.97,-7.62; 2 -11.43,-7.62; 3 -8.89,-7.62; 4 -6.35,-7.62; 5 -3.81,-7.62; 6 -1.27,-7.62; 7 1.27,-7.62; 8 3.81,-7.62; 9 6.35,-7.62; 10 8.89,-7.62; 11 11.43,-7.62; 12 13.97,-7.62; 13 13.97,7.62; 14 11.43,7.62; 15 8.89,7.62; 16 6.35,7.62; 17 3.81,7.62; 18 1.27,7.62; 19 -1.27,7.62; 20 -3.81,7.62; 21 -6.35,7.62; 22 -8.89,7.62; 23 -11.43,7.62; 24 -13.97,7.62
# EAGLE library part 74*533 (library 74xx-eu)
Inverting 8-bit D type LATCH

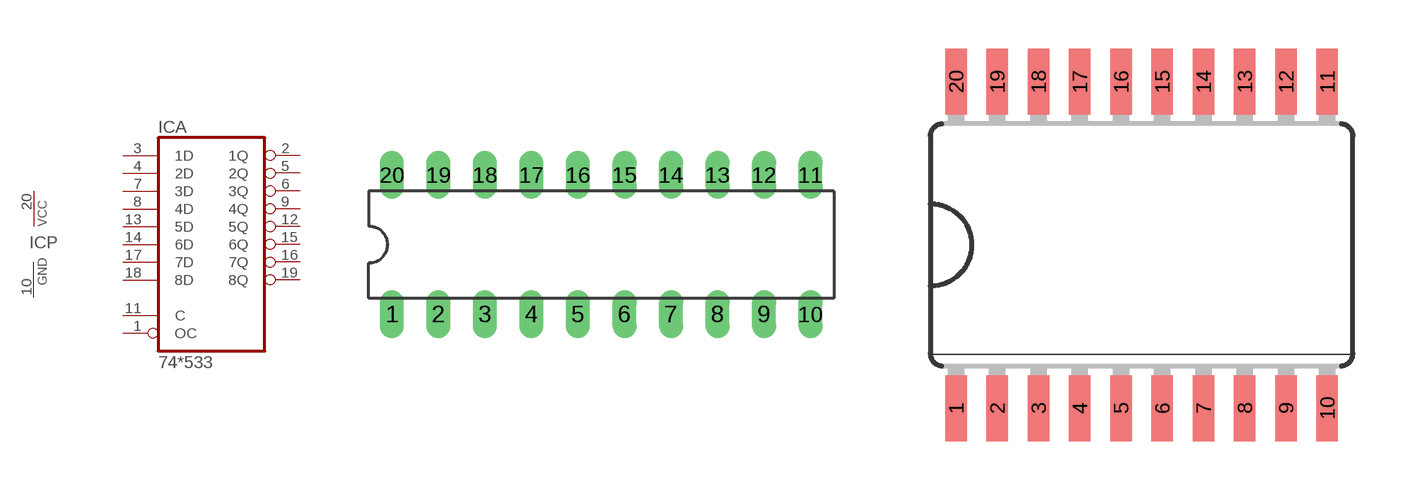
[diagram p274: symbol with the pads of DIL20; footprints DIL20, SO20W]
Designator prefix IC; gates A=74533 P=PWRN

## 74AC533N, 74ACT533N, 74ALS533N, 74HC533N, 74HCT533N  [DIL20]
1  A:OC  in
2  A:1Q  hiz
3  A:1D  in
4  A:2D  in
5  A:2Q  hiz
6  A:3Q  hiz
7  A:3D  in
8  A:4D  in
9  A:4Q  hiz
10  P:GND  pwr
11  A:C  in
12  A:5Q  hiz
13  A:5D  in
14  A:6D  in
15  A:6Q  hiz
16  A:7Q  hiz
17  A:7D  in
18  A:8D  in
19  A:8Q  hiz
20  P:VCC  pwr

## 74AC533D, 74ACT533D, 74HC533D, 74HCT533D  [SO20W]
Pads as for DIL20

## Footprint DIL20 (pad centres in mm)
Dual In Line Package
drill 0.813 long: 1 -11.43,-3.81; 2 -8.89,-3.81; 3 -6.35,-3.81; 4 -3.81,-3.81; 5 -1.27,-3.81; 6 1.27,-3.81; 7 3.81,-3.81; 8 6.35,-3.81; 9 8.89,-3.81; 10 11.43,-3.81; 11 11.43,3.81; 12 8.89,3.81; 13 6.35,3.81; 14 3.81,3.81; 15 1.27,3.81; 16 -1.27,3.81; 17 -3.81,3.81; 18 -6.35,3.81; 19 -8.89,3.81; 20 -11.43,3.81

## Footprint SO20W (pad centres in mm)
Wide Small Outline package 300 mil
smd 0.66 x 2.032: 1 -5.715,-5.029; 2 -4.445,-5.029; 3 -3.175,-5.029; 4 -1.905,-5.029; 5 -0.635,-5.029; 6 0.635,-5.029; 7 1.905,-5.029; 8 3.175,-5.029; 9 4.445,-5.029; 10 5.715,-5.029; 11 5.715,5.029; 12 4.445,5.029; 13 3.175,5.029; 14 1.905,5.029; 15 0.635,5.029; 16 -0.635,5.029; 17 -1.905,5.029; 18 -3.175,5.029; 19 -4.445,5.029; 20 -5.715,5.029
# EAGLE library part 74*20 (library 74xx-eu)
Dual 4-input NAND gate

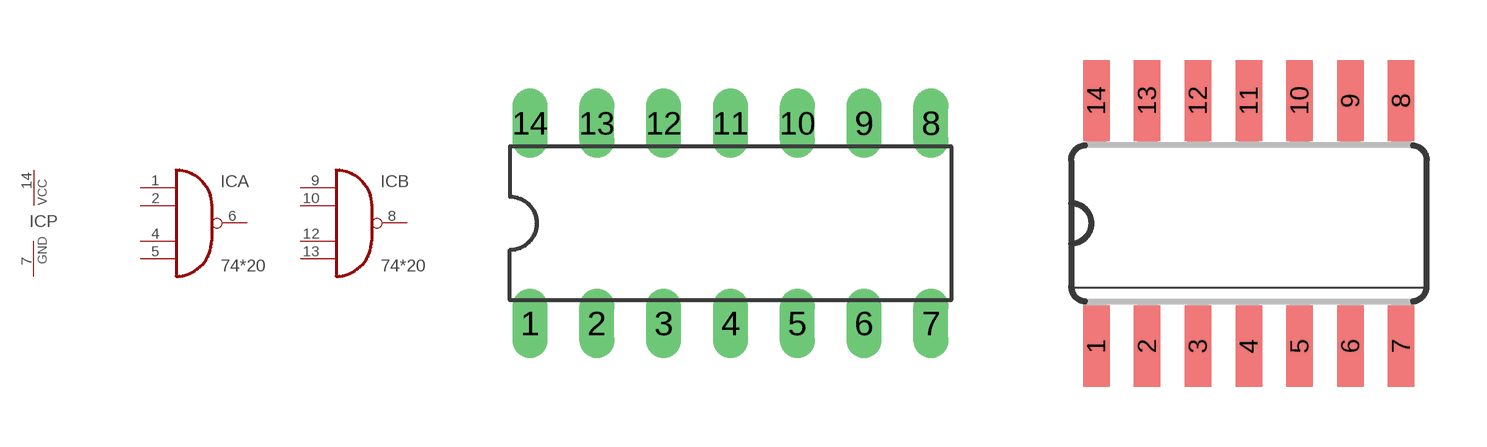
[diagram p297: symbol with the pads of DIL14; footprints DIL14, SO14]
Designator prefix IC; gates A=7420 B=7420 P=PWRN

## 74AC20N, 74ACT20N, 74ALS20N, 74AS20N, 74HC20N, 74HCT20N, 74LS20N, 74S20N  [DIL14]
1  A:I0  in
2  A:I1  in
4  A:I2  in
5  A:I3  in
6  A:O  out
7  P:GND  pwr
8  B:O  out
9  B:I0  in
10  B:I1  in
12  B:I2  in
13  B:I3  in
14  P:VCC  pwr

## 74AC20D, 74ACT20D, 74ALS20D, 74AS20D, 74HC20D, 74HCT20D, 74LS20D, 74S20D  [SO14]
Pads as for DIL14

## 74AC20FK, 74ACT20FK, 74ALS20FK, 74AS20FK, 74HC20FK, 74HCT20FK, 74LS20FK, 74S20FK  [LCC20]
2  A:I0  in
3  A:I1  in
6  A:I2  in
8  A:I3  in
9  A:O  out
10  P:GND  pwr
12  B:O  out
13  B:I0  in
14  B:I1  in
18  B:I2  in
19  B:I3  in
20  P:VCC  pwr

## Footprint DIL14 (pad centres in mm)
Dual In Line Package
drill 0.813 long: 1 -7.62,-3.81; 2 -5.08,-3.81; 3 -2.54,-3.81; 4 0,-3.81; 5 2.54,-3.81; 6 5.08,-3.81; 7 7.62,-3.81; 8 7.62,3.81; 9 5.08,3.81; 10 2.54,3.81; 11 0,3.81; 12 -2.54,3.81; 13 -5.08,3.81; 14 -7.62,3.81

## Footprint SO14 (pad centres in mm)
Small Outline package 150 mil
smd 0.66 x 2.032: 1 -3.81,-3.073; 2 -2.54,-3.073; 3 -1.27,-3.073; 4 0,-3.073; 5 1.27,-3.073; 6 2.54,-3.073; 7 3.81,-3.073; 8 3.81,3.073; 9 2.54,3.073; 10 1.27,3.073; 11 0,3.073; 12 -1.27,3.073; 13 -2.54,3.073; 14 -3.81,3.073

## Footprint LCC20 (pad centres in mm)
Leadless Chip Carrier Ceramic Package
smd 0.8 x 3.4: 1 0,3.8
smd 0.8 x 2: 2 -1.27,4.5; 3 -2.54,4.5; 9 -2.54,-4.5; 10 -1.27,-4.5; 11 0,-4.5; 12 1.27,-4.5; 13 2.54,-4.5; 19 2.54,4.5; 20 1.27,4.5
smd 2 x 0.8: 4 -4.5,2.54; 5 -4.5,1.27; 6 -4.5,0; 7 -4.5,-1.27; 8 -4.5,-2.54; 14 4.5,-2.54; 15 4.5,-1.27; 16 4.5,0; 17 4.5,1.27; 18 4.5,2.54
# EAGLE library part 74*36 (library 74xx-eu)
Quad 2-input NOR gate

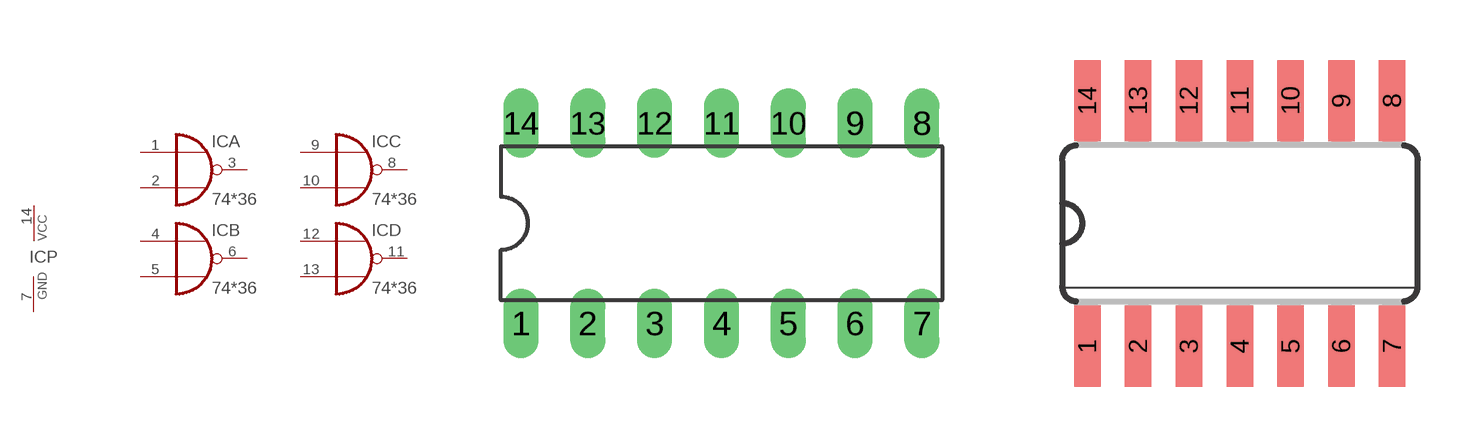
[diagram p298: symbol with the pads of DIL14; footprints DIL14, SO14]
Designator prefix IC; gates A=7436 B=7436 C=7436 D=7436 P=PWRN

## 7436N  [DIL14]
1  A:I0  in
2  A:I1  in
3  A:O  out
4  B:I0  in
5  B:I1  in
6  B:O  out
7  P:GND  pwr
8  C:O  out
9  C:I0  in
10  C:I1  in
11  D:O  out
12  D:I0  in
13  D:I1  in
14  P:VCC  pwr

## 7436D  [SO14]
Pads as for DIL14

## Footprint DIL14 (pad centres in mm)
Dual In Line Package
drill 0.813 long: 1 -7.62,-3.81; 2 -5.08,-3.81; 3 -2.54,-3.81; 4 0,-3.81; 5 2.54,-3.81; 6 5.08,-3.81; 7 7.62,-3.81; 8 7.62,3.81; 9 5.08,3.81; 10 2.54,3.81; 11 0,3.81; 12 -2.54,3.81; 13 -5.08,3.81; 14 -7.62,3.81

## Footprint SO14 (pad centres in mm)
Small Outline package 150 mil
smd 0.66 x 2.032: 1 -3.81,-3.073; 2 -2.54,-3.073; 3 -1.27,-3.073; 4 0,-3.073; 5 1.27,-3.073; 6 2.54,-3.073; 7 3.81,-3.073; 8 3.81,3.073; 9 2.54,3.073; 10 1.27,3.073; 11 0,3.073; 12 -1.27,3.073; 13 -2.54,3.073; 14 -3.81,3.073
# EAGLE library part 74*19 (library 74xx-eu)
Hex schmitt trigger INVERTER

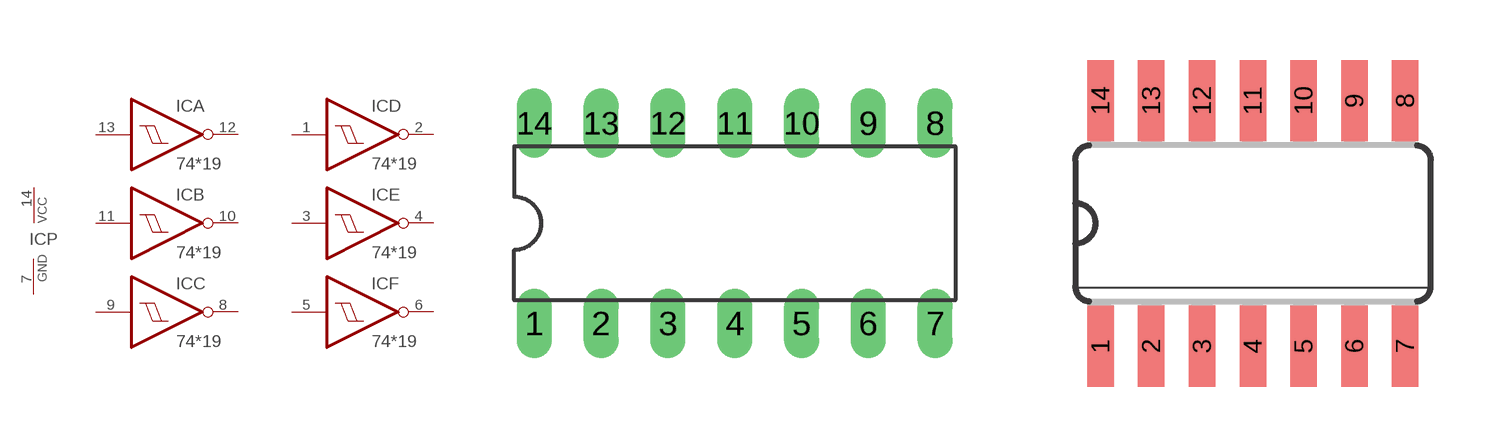
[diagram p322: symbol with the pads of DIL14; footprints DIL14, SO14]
Designator prefix IC; gates A=7414 B=7414 C=7414 D=7414 E=7414 F=7414 P=PWRN

## 74HC19N, 74HCT19N, 74LS19N  [DIL14]
1  D:I  in
2  D:O  out
3  E:I  in
4  E:O  out
5  F:I  in
6  F:O  out
7  P:GND  pwr
8  C:O  out
9  C:I  in
10  B:O  out
11  B:I  in
12  A:O  out
13  A:I  in
14  P:VCC  pwr

## 74HC19D, 74HCT19D, 74LS19D  [SO14]
Pads as for DIL14

## Footprint DIL14 (pad centres in mm)
Dual In Line Package
drill 0.813 long: 1 -7.62,-3.81; 2 -5.08,-3.81; 3 -2.54,-3.81; 4 0,-3.81; 5 2.54,-3.81; 6 5.08,-3.81; 7 7.62,-3.81; 8 7.62,3.81; 9 5.08,3.81; 10 2.54,3.81; 11 0,3.81; 12 -2.54,3.81; 13 -5.08,3.81; 14 -7.62,3.81

## Footprint SO14 (pad centres in mm)
Small Outline package 150 mil
smd 0.66 x 2.032: 1 -3.81,-3.073; 2 -2.54,-3.073; 3 -1.27,-3.073; 4 0,-3.073; 5 1.27,-3.073; 6 2.54,-3.073; 7 3.81,-3.073; 8 3.81,3.073; 9 2.54,3.073; 10 1.27,3.073; 11 0,3.073; 12 -1.27,3.073; 13 -2.54,3.073; 14 -3.81,3.073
